VERSION 5.8 ;
BUSBITCHARS "<>" ;
DIVIDERCHAR "/" ;

UNITS
   DATABASE MICRONS 1000 ;
END UNITS

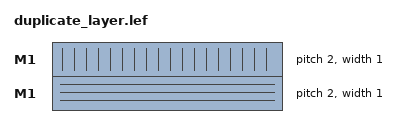
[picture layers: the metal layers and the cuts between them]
LAYER M1
   TYPE ROUTING ;
   WIDTH 1 ;
   PITCH 2 ;
   DIRECTION HORIZONTAL ;
END M1

LAYER M1
   TYPE ROUTING ;
   WIDTH 1 ;
   PITCH 2 ;
   DIRECTION VERTICAL ;
END M1
